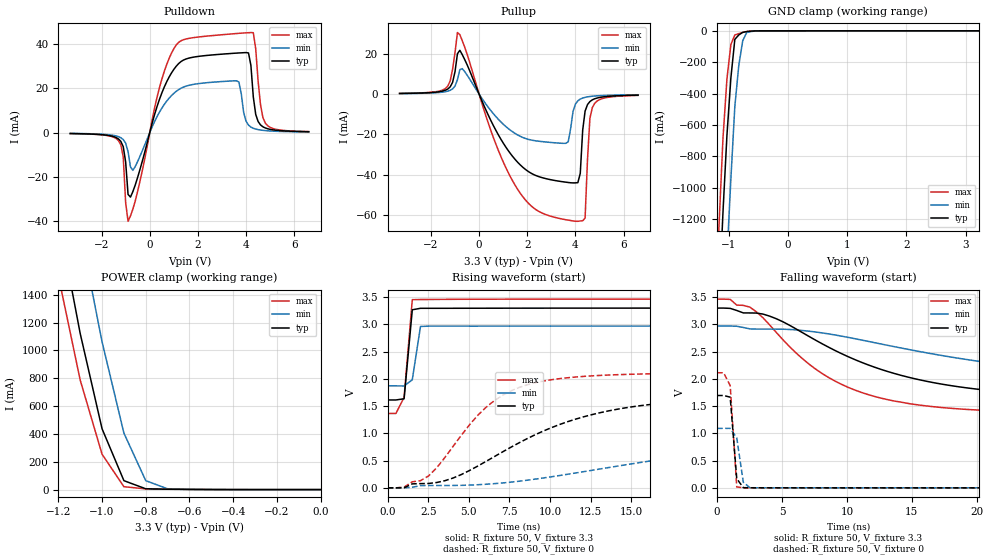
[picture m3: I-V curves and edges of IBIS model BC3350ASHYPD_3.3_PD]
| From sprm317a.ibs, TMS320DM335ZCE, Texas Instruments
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|   Component BC3350ASHYPD
|   Model Cell BC3350ASHYPD_3.3_PD
[Model]   BC3350ASHYPD_3.3_PD
Model_type   I/O
Polarity   Non-Inverting
Enable   Active-Low
Vinl =  1.5
Vinh =  1.8
Cref =  15.0000pF
Rref =  100.0000M
Vref =  0V
Vmeas =  1.65
C_comp   0.972592p   0.9599789p   0.9808023p
[Model Spec]
Vinl   1.5   1.335   1.5825
Vinh   1.8   1.635   1.8825
[Temperature Range]   25   125   -40
[Voltage Range]   3.3   2.97   3.465
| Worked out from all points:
|   slope of the pulldown table from 0 to 0.495 V, typ, clamps not added: 27.9 ohm
|   slope of the pullup table from 0 to 0.495 V, typ, clamps not added: 37.2 ohm
|   GND clamp passes 1 mA (typ) near -0.58 V on its own axis
|   POWER clamp passes 1 mA (typ) near -0.54 V on its own axis
|   rising waveform, R_fixture 50, V_fixture 3.3: 20-80 % time 313ps typ, 340ps min, 355ps max; typ from 1.61 V to 3.3 V
|   rising waveform, R_fixture 50, V_fixture 0: 20-80 % time 7.58ns typ, 16.6ns min, 3.87ns max; typ from 0 V to 1.69 V
|   falling waveform, R_fixture 50, V_fixture 3.3: 20-80 % time 10.4ns typ, 17.4ns min, 6.89ns max; typ from 3.3 V to 1.62 V
|   falling waveform, R_fixture 50, V_fixture 0: 20-80 % time 343ps typ, 407ps min, 344ps max; typ from 1.69 V to 0 V
[POWER_clamp]
|   voltage   I(typ)   I(min)   I(max)
-3.3V     22.26A     22.97A     21.87A
-1.2V     1.948A     2.725A     1.537A
-1.167V   1.673A     2.438A     1.287A
-1.133V   1.398A     2.15A      1.037A
-1.1V     1.122A     1.862A     787.5mA
-1.067V   894.2mA    1.595A     609.9mA
-1.033V   665.9mA    1.329A     432.2mA
-1V       437.5mA    1.062A     254.6mA
-900mV    64.3mA     406.1mA    20.83mA
-800mV    5.858mA    64.2mA     5.344mA
-700mV    2.683mA    5.806mA    3.281mA
-11.55fV  98.21uA    49.4uA     162.3uA
[Pulldown]
|   voltage   I(typ)   I(min)   I(max)
-3.3V     -400.6uA   -325.7uA   -416.4uA
-1.3V     -2.82mA    -1.791mA   -3.561mA
-1.1V     -6.344mA   -3.117mA   -10.94mA
-900mV    -27.92mA   -8.557mA   -40.06mA
-700mV    -26.62mA   -17.04mA   -34.57mA
400mV     14.94mA    9.202mA    20.18mA
1.1V      30.02mA    18.67mA    39.63mA
3.7V      36.02mA    22.92mA    44.89mA
4.2V      30.44mA    2.528mA    45.24mA
4.4V      8.262mA    1.627mA    37.92mA
4.8V      2.109mA    932uA      4.312mA
6.6V      432uA      310.9uA    478.4uA
[Pullup]
|   voltage   I(typ)   I(min)   I(max)
-3.3V     327.2uA    258.8uA    367uA
-1.3V     2.537mA    1.47mA     3.99mA
-900mV    20.03mA    7.177mA    30.58mA
-700mV    19.64mA    12.67mA    26.58mA
1.6V      -33.86mA   -20.29mA   -47.32mA
3.6V      -43.76mA   -24.45mA   -62.41mA
4.1V      -43.98mA   -3.317mA   -63.2mA
4.2V      -39.34mA   -2.467mA   -63.03mA
4.4V      -8.449mA   -1.61mA    -61.61mA
4.6V      -3.699mA   -1.187mA   -12mA
4.7V      -2.851mA   -1.047mA   -6.689mA
6.6V      -510.2uA   -319.1uA   -633uA
[GND_clamp]
|   voltage   I(typ)   I(min)   I(max)
-3.3V     -22.38A    -23.14A    -21.96A
-1.167V   -1.723A    -2.572A    -1.235A
-1.1V     -1.153A    -1.989A    -682mA
-1.033V   -666.3mA   -1.445A    -305.8mA
-966.7mV  -300mA     -942.5mA   -87.3mA
-900mV    -54.51mA   -482.5mA   -26.52mA
-833.3mV  -26.33mA   -220.7mA   -17.73mA
-766.7mV  -9.699mA   -63.44mA   -10.39mA
-700mV    -4.622mA   -10.61mA   -4.493mA
-566.7mV  -734.7uA   -1.505mA   -502.3uA
-433.3mV  -74.68uA   -170.1uA   -70.93uA
3.233V    98.2uA     61.6uA     162.2uA
[Ramp]
| variable   typ   min   max
dV/dt_f   1.009973/10.44558n   0.6341346/17.38728n   1.259403/6.880976n
dV/dt_r   1.016554/7.573793n   0.6368825/16.64163n   1.267372/3.857587n
R_load = 50
[Rising Waveform]
R_fixture = 50
V_fixture = 3.3
V_fixture_min = 2.97
V_fixture_max = 3.465
| time   V(typ)   V(min)   V(max)
|   time   V(typ)   V(min)   V(max)
0s        1.612V     1.871V     1.365V
505.1ps   1.612V     1.871V     1.365V
1.01ns    1.634V     1.87V      1.66V
1.515ns   3.267V     1.983V     3.452V
2.02ns    3.294V     2.96V      3.455V
2.525ns   3.294V     2.967V     3.456V
50ns      3.298V     2.969V     3.462V
[Rising Waveform]
R_fixture = 50
V_fixture = 0
V_fixture_min = 0
V_fixture_max = 0
| time   V(typ)   V(min)   V(max)
|   time   V(typ)   V(min)   V(max)
0s        57.9nV     466.6nV    5.467nV
2.525ns   80.82mV    43.28mV    220.2mV
4.04ns    181.8mV    43.91mV    765.9mV
6.566ns   572.3mV    76.97mV    1.599V
8.081ns   824.4mV    121.6mV    1.84V
10.1ns    1.106V     204mV      1.984V
14.14ns   1.442V     398.2mV    2.076V
19.7ns    1.61V      638.7mV    2.104V
32.32ns   1.684V     943.2mV    2.112V
50ns      1.694V     1.061V     2.112V
[Falling Waveform]
R_fixture = 50
V_fixture = 3.3
V_fixture_min = 2.97
V_fixture_max = 3.465
| time   V(typ)   V(min)   V(max)
|   time   V(typ)   V(min)   V(max)
0s        3.298V     2.969V     3.462V
2.525ns   3.209V     2.916V     3.316V
4.04ns    3.151V     2.912V     2.991V
6.566ns   2.849V     2.887V     2.371V
9.091ns   2.519V     2.804V     1.958V
11.62ns   2.258V     2.688V     1.712V
14.65ns   2.035V     2.544V     1.551V
19.7ns    1.82V      2.337V     1.433V
25.76ns   1.703V     2.163V     1.386V
50ns      1.616V     1.913V     1.365V
[Falling Waveform]
R_fixture = 50
V_fixture = 0
V_fixture_min = 0
V_fixture_max = 0
| time   V(typ)   V(min)   V(max)
|   time   V(typ)   V(min)   V(max)
0s        1.694V     1.091V     2.112V
505.1ps   1.694V     1.091V     2.112V
1.01ns    1.664V     1.092V     1.876V
1.515ns   169mV      915.3mV    16.5mV
2.02ns    3.416mV    103.3mV    2.289mV
2.525ns   1.446mV    3.7mV      1.33mV
50ns      922.3nV    11.66uV    68.52nV
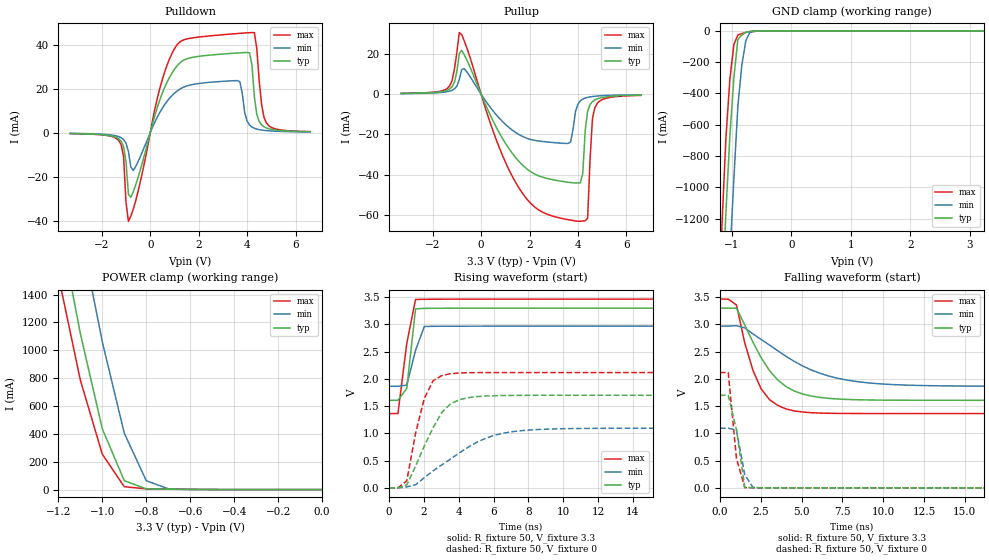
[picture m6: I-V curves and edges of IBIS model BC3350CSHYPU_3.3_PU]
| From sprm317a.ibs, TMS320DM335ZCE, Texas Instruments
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|   GS50 Cell BC3350CSHYPU
|   Model Cell BC3350CSHYPU_3.3_PU
[Model]   BC3350CSHYPU_3.3_PU
Model_type   I/O
Polarity   Non-Inverting
Enable   Active-Low
Vinl =  1.5
Vinh =  1.8
Cref =  15.0000pF
Rref =  100.0000M
Vref =  0V
Vmeas =  1.65
C_comp   0.972592p   0.9599789p   0.9808023p
[Model Spec]
Vinl   1.5   1.335   1.5825
Vinh   1.8   1.635   1.8825
[Temperature Range]   25   125   -40
[Voltage Range]   3.3   2.97   3.465
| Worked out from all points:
|   slope of the pulldown table from 0 to 0.495 V, typ, clamps not added: 27.7 ohm
|   slope of the pullup table from 0 to 0.495 V, typ, clamps not added: 37.2 ohm
|   GND clamp passes 1 mA (typ) near -0.58 V on its own axis
|   POWER clamp passes 1 mA (typ) near -0.55 V on its own axis
|   rising waveform, R_fixture 50, V_fixture 3.3: 20-80 % time 351ps typ, 605ps min, 587ps max; typ from 1.61 V to 3.3 V
|   rising waveform, R_fixture 50, V_fixture 0: 20-80 % time 1.55ns typ, 3.16ns min, 917ps max; typ from 0.001 V to 1.7 V
|   falling waveform, R_fixture 50, V_fixture 3.3: 20-80 % time 2.12ns typ, 3.91ns min, 1.37ns max; typ from 3.3 V to 1.61 V
|   falling waveform, R_fixture 50, V_fixture 0: 20-80 % time 582ps typ, 444ps min, 479ps max; typ from 1.7 V to 0.001 V
[POWER_clamp]
|   voltage   I(typ)   I(min)   I(max)
-3.3V     22.26A     22.97A     21.87A
-1.2V     1.947A     2.724A     1.536A
-1.167V   1.672A     2.436A     1.287A
-1.133V   1.397A     2.148A     1.037A
-1.1V     1.122A     1.86A      787.1mA
-1.067V   893.3mA    1.594A     609.5mA
-1.033V   665.2mA    1.327A     432mA
-1V       437mA      1.061A     254.5mA
-900mV    64.21mA    405.2mA    20.8mA
-800mV    5.835mA    63.97mA    5.284mA
-700mV    2.647mA    5.786mA    3.202mA
-11.55fV  459.3pA    9.252nA    230.6pA
[Pulldown]
|   voltage   I(typ)   I(min)   I(max)
-3.3V     -403.6uA   -328.8uA   -418.9uA
-1.3V     -2.841mA   -1.807mA   -3.581mA
-1.1V     -6.386mA   -3.145mA   -10.99mA
-900mV    -28.11mA   -8.625mA   -40.3mA
-700mV    -26.82mA   -17.2mA    -34.77mA
400mV     15.05mA    9.288mA    20.3mA
1.1V      30.25mA    18.85mA    39.86mA
3.7V      36.3mA     23.15mA    45.16mA
4.2V      30.68mA    2.555mA    45.51mA
4.4V      8.338mA    1.643mA    38.15mA
4.8V      2.127mA    941.5uA    4.342mA
6.6V      435.4uA    314uA      481.3uA
[Pullup]
|   voltage   I(typ)   I(min)   I(max)
-3.3V     327.4uA    259.3uA    367uA
-1.3V     2.541mA    1.473mA    3.994mA
-900mV    20.05mA    7.198mA    30.58mA
-700mV    19.65mA    12.69mA    26.57mA
1.6V      -33.88mA   -20.32mA   -47.31mA
3.6V      -43.79mA   -24.49mA   -62.4mA
4.1V      -44.01mA   -3.32mA    -63.19mA
4.2V      -39.34mA   -2.47mA    -63.02mA
4.4V      -8.445mA   -1.612mA   -61.59mA
4.6V      -3.699mA   -1.188mA   -11.99mA
4.7V      -2.851mA   -1.049mA   -6.684mA
6.6V      -510.5uA   -319.6uA   -632.9uA
[GND_clamp]
|   voltage   I(typ)   I(min)   I(max)
-3.3V     -22.38A    -23.15A    -21.96A
-1.167V   -1.724A    -2.574A    -1.236A
-1.1V     -1.155A    -1.991A    -683mA
-1.033V   -667.4mA   -1.447A    -306.4mA
-966.7mV  -300.8mA   -944.1mA   -87.57mA
-900mV    -54.73mA   -483.8mA   -26.57mA
-833.3mV  -26.43mA   -221.5mA   -17.78mA
-766.7mV  -9.741mA   -63.74mA   -10.43mA
-700mV    -4.66mA    -10.67mA   -4.538mA
-566.7mV  -780uA     -1.533mA   -563.3uA
-433.3mV  -131.6uA   -202.5uA   -150.5uA
3.233V    -4.373uA   23.83uA    -20.78uA
[Ramp]
| variable   typ   min   max
dV/dt_f   1.026357/2.114875n   0.6713871/3.942626n   1.272714/1.373508n
dV/dt_r   1.019438/1.521913n   0.6572379/3.143127n   1.269831/0.9080105n
R_load = 50
[Rising Waveform]
R_fixture = 50
V_fixture = 3.3
V_fixture_min = 2.97
V_fixture_max = 3.465
| time   V(typ)   V(min)   V(max)
|   time   V(typ)   V(min)   V(max)
0s        1.608V     1.865V     1.365V
505.1ps   1.608V     1.865V     1.365V
1.01ns    1.825V     1.886V     2.647V
1.515ns   3.286V     2.526V     3.459V
2.02ns    3.296V     2.963V     3.462V
50ns      3.3V       2.97V      3.465V
[Rising Waveform]
R_fixture = 50
V_fixture = 0
V_fixture_min = 0
V_fixture_max = 0
| time   V(typ)   V(min)   V(max)
|   time   V(typ)   V(min)   V(max)
0s        1.449mV    1.131mV    1.679mV
505.1ps   1.443mV    1.131mV    1.417mV
1.01ns    54.33mV    18.28mV    128.2mV
1.515ns   396.7mV    58.1mV     1.001V
2.02ns    769.8mV    188.1mV    1.644V
2.525ns   1.106V     314.4mV    1.967V
3.535ns   1.545V     532.7mV    2.096V
6.061ns   1.693V     966.8mV    2.117V
9.091ns   1.7V       1.079V     2.118V
50ns      1.7V       1.096V     2.118V
[Falling Waveform]
R_fixture = 50
V_fixture = 3.3
V_fixture_min = 2.97
V_fixture_max = 3.465
| time   V(typ)   V(min)   V(max)
|   time   V(typ)   V(min)   V(max)
0s        3.3V       2.97V      3.465V
1.01ns    3.298V     2.978V     3.358V
1.515ns   2.991V     2.937V     2.665V
2.02ns    2.674V     2.827V     2.157V
2.525ns   2.387V     2.723V     1.817V
3.535ns   1.983V     2.518V     1.515V
4.545ns   1.779V     2.323V     1.414V
7.576ns   1.626V     1.99V      1.367V
11.62ns   1.609V     1.885V     1.365V
50ns      1.608V     1.865V     1.365V
[Falling Waveform]
R_fixture = 50
V_fixture = 0
V_fixture_min = 0
V_fixture_max = 0
| time   V(typ)   V(min)   V(max)
|   time   V(typ)   V(min)   V(max)
0s        1.7V       1.096V     2.118V
505.1ps   1.7V       1.096V     2.118V
1.01ns    1.068V     1.059V     541.5mV
1.515ns   15.55mV    243.8mV    5.114mV
2.02ns    4.02mV     10.46mV    3.095mV
2.525ns   2.953mV    3.797mV    2.434mV
50ns      1.449mV    1.131mV    1.679mV
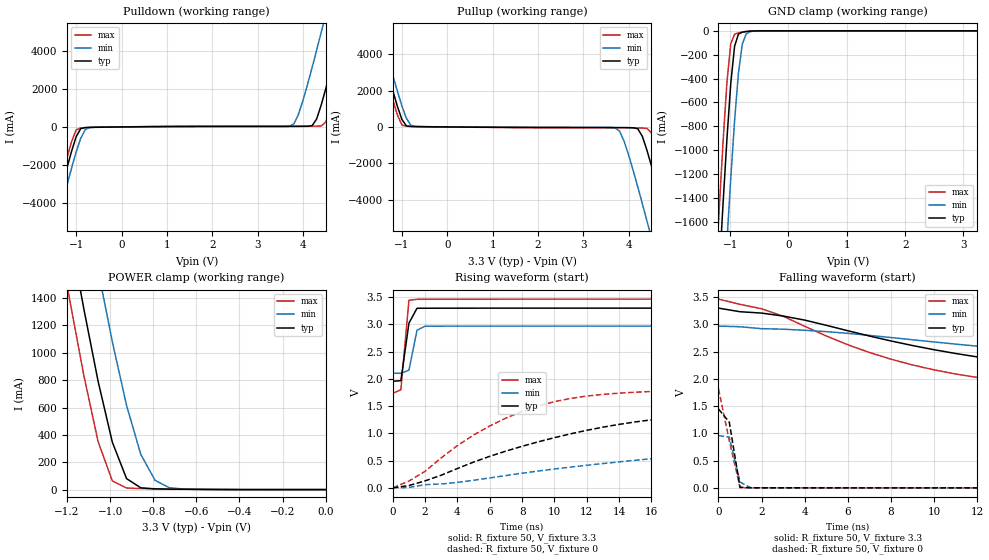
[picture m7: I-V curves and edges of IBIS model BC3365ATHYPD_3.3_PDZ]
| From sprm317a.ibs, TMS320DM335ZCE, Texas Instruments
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|   Component BC3365ATHYPD
|   Model Cell BC3365ATHYPD_3.3_PDZ
[Model]   BC3365ATHYPD_3.3_PDZ
Model_type   I/O
Polarity   Non-Inverting
Enable   Active-Low
Vinl =  1.5
Vinh =  1.8
Cref =  15.0000pF
Rref =  100.0000M
Vref =  0V
Vmeas =  1.65
C_comp   1.4550p   1.4591p   1.4542p
[Model Spec]
Vinl   1.5   1.335   1.5825
Vinh   1.8   1.635   1.8825
[Temperature Range]   25   125   -40
[Voltage Range]   3.3   2.97   3.465
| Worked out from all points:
|   slope of the pulldown table from 0 to 0.495 V, typ, clamps not added: 39.2 ohm
|   slope of the pullup table from 0 to 0.495 V, typ, clamps not added: 46.8 ohm
|   GND clamp passes 1 mA (typ) near -0.58 V on its own axis
|   POWER clamp passes 1 mA (typ) near -0.52 V on its own axis
|   rising waveform, R_fixture 50, V_fixture 3.3: 20-80 % time 389ps typ, 354ps min, 315ps max; typ from 1.96 V to 3.3 V
|   rising waveform, R_fixture 50, V_fixture 0: 20-80 % time 10.4ns typ, 19.8ns min, 6.25ns max; typ from 0 V to 1.45 V
|   falling waveform, R_fixture 50, V_fixture 3.3: 20-80 % time 11.2ns typ, 17.3ns min, 7.97ns max; typ from 3.3 V to 1.96 V
|   falling waveform, R_fixture 50, V_fixture 0: 20-80 % time 363ps typ, 348ps min, 601ps max; typ from 1.45 V to 0 V
[POWER_clamp]
|   voltage   I(typ)   I(min)   I(max)
-3.3V     22.37A     23.13A     21.95A
-1.254V   2.477A     3.334A     1.977A
-1.188V   1.887A     2.741A     1.389A
-1.122V   1.32A      2.163A     832.6mA
-1.056V   791.8mA    1.605A     350.4mA
-990mV    346.9mA    1.081A     63.79mA
-924mV    80.36mA    615.5mA    11.8mA
-858mV    13.13mA    257.6mA    7.543mA
-792mV    5.189mA    68.08mA    5.819mA
-726mV    3.556mA    14.04mA    4.359mA
-660mV    2.551mA    3.956mA    3.077mA
-7.994fV  477.5pA    13.59nA    225.3pA
[Pulldown]
|   voltage   I(typ)   I(min)   I(max)
-3.3V     -22.52A    -23.33A    -22.07A
-1.6V     -5.868A    -6.754A    -5.356A
-1.4V     -3.969A    -4.867A    -3.446A
-1.1V     -1.269A    -2.15A     -763.7mA
-900mV    -91.22mA   -600mA     -51.47mA
3.7V      28.47mA    32.98mA    36.63mA
3.9V      30.18mA    660.8mA    37.1mA
4.2V      65.76mA    3.119A     41.65mA
4.4V      1.143A     4.959A     50.6mA
4.8V      4.77A      8.763A     2.725A
5.1V      7.648A     11.66A     5.579A
6.6V      22.37A     26.38A     20.32A
[Pullup]
|   voltage   I(typ)   I(min)   I(max)
-3.3V     22.37A     23.13A     21.95A
-1.6V     5.722A     6.562A     5.242A
-1.5V     4.769A     5.616A     4.283A
-1V       414.3mA    1.161A     109.5mA
-700mV    19.39mA    18.75mA    25.39mA
3.7V      -34.43mA   -48.34mA   -45.92mA
3.9V      -35.85mA   -799.7mA   -46.23mA
4.2V      -101.1mA   -3.302A    -52.47mA
4.4V      -1.271A    -5.148A    -77.72mA
4.8V      -4.914A    -8.957A    -2.837A
5.1V      -7.794A    -11.86A    -5.694A
6.6V      -22.52A    -26.58A    -20.44A
[GND_clamp]
|   voltage   I(typ)   I(min)   I(max)
-3.3V     -22.52A    -23.33A    -22.07A
-1.254V   -2.615A    -3.518A    -2.087A
-1.188V   -2.022A    -2.922A    -1.495A
-1.122V   -1.449A    -2.338A    -932.9mA
-1.056V   -911mA     -1.774A    -435.1mA
-990mV    -443mA     -1.238A    -107.9mA
-924mV    -129.2mA   -751.9mA   -28.6mA
-858mV    -27.62mA   -355.1mA   -17.13mA
-792mV    -11.17mA   -111.8mA   -10.6mA
-726mV    -6.073mA   -26.07mA   -5.56mA
-660mV    -2.955mA   -7.156mA   -2.197mA
3.234V    -812.5pA   32.73uA    163.9pA
[Ramp]
| variable   typ   min   max
dV/dt_f   0.8063/11.2910n   0.5193/17.3295n   1.0372/7.9905n
dV/dt_r   0.8690/10.4137n   0.5758/19.8425n   1.0894/6.2291n
R_load = 50
[Rising Waveform]
R_fixture = 50
V_fixture = 3.3
V_fixture_min = 2.97
V_fixture_max = 3.465
| time   V(typ)   V(min)   V(max)
0s        1.958V     2.104V     1.736V
500ps     1.968V     2.103V     1.8V
1ns       3.026V     2.16V      3.445V
1.5ns     3.297V     2.895V     3.462V
2ns       3.298V     2.968V     3.463V
49.5ns    3.3V       2.97V      3.465V
[Rising Waveform]
R_fixture = 50
V_fixture = 0
V_fixture_min = 0
V_fixture_max = 0
|   time   V(typ)   V(min)   V(max)
0s        0V         0V         0V
2ns       128.3mV    58.6mV     304.5mV
4ns       355.5mV    100.7mV    776.8mV
7ns       675mV      226.4mV    1.281V
10ns      921.4mV    346.3mV    1.583V
14ns      1.165V     477mV      1.739V
18ns      1.309V     590mV      1.788V
22ns      1.379V     687.8mV    1.805V
39ns      1.444V     905.1mV    1.816V
99ns      1.448V     959.6mV    1.816V
[Falling Waveform]
R_fixture = 50
V_fixture = 3.3
V_fixture_min = 2.97
V_fixture_max = 3.465
|   time   V(typ)   V(min)   V(max)
0s        3.3V       2.97V      3.465V
2ns       3.209V     2.922V     3.288V
4ns       3.08V      2.893V     2.967V
6ns       2.885V     2.837V     2.628V
9ns       2.613V     2.719V     2.257V
13ns      2.349V     2.565V     1.974V
18ns      2.151V     2.41V      1.822V
26ns      2.017V     2.253V     1.753V
40ns      1.965V     2.143V     1.737V
99ns      1.958V     2.104V     1.736V
[Falling Waveform]
R_fixture = 50
V_fixture = 0
V_fixture_min = 0
V_fixture_max = 0
|   time   V(typ)   V(min)   V(max)
0s        1.448V     959.7mV    1.816V
500ps     1.207V     931.9mV    870mV
1ns       10.5mV     105.6mV    4mV
1.5ns     1.6mV      2mV        2mV
2ns       1.1mV      800uV      1mV
49.5ns    0V         0V         0V
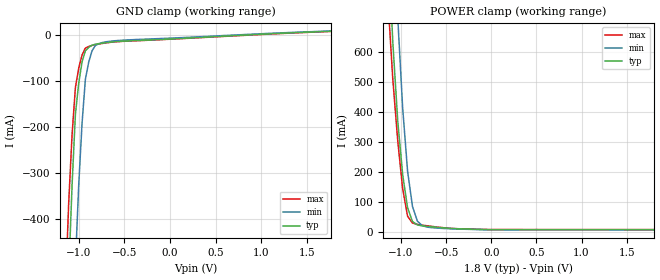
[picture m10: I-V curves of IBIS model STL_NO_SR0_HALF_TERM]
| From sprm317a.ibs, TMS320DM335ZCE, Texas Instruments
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|   Model Cell STL_NO_SR0_HALF_TERM
[Model]   STL_NO_SR0_HALF_TERM
Model_type   Input
Polarity   Non-Inverting
Vinl =  0.80
Vinh =  1.00
C_comp   2.680301p   2.549919p   2.900942p
[Model Spec]
Vinl   0.80   0.71   0.89
Vinh   1.00   0.91   1.09
[Temperature Range]   25   125   -40
[Voltage Range]   1.8   1.62   1.89
[POWER_clamp]
|   voltage   I(typ)   I(min)   I(max)
-1.8V     6.874A     7.433A     6.581A
-1.127V   863.6mA    1.359A     685.9mA
-1.109V   748mA      1.221A     597.3mA
-1.091V   632.5mA    1.084A     508.8mA
-1.036V   370.2mA    715.1mA    304.1mA
-1.018V   310.5mA    614.6mA    250.8mA
-981.8mV  191.1mA    413.7mA    144.1mA
-927.3mV  80.75mA    202.4mA    52.31mA
-872.7mV  34.47mA    84.58mA    29.44mA
-818.2mV  23.28mA    35.89mA    25.1mA
-654.5mV  16.79mA    14.05mA    18.26mA
1.8V      7.556mA    6.792mA    7.728mA
[GND_clamp]
|   voltage   I(typ)   I(min)   I(max)
-1.8V     -6.676A    -7.172A    -6.432A
-1.145V   -748.6mA   -1.247A    -551.2mA
-1.109V   -517.7mA   -978.2mA   -362.4mA
-1.073V   -325.9mA   -728.6mA   -216.9mA
-1.036V   -172.9mA   -497.6mA   -114.9mA
-1V       -105.1mA   -326.1mA   -72.69mA
-963.6mV  -59.22mA   -192.7mA   -44.16mA
-927.3mV  -35.2mA    -97.13mA   -29.3mA
-854.5mV  -23.13mA   -35.34mA   -23.48mA
-818.2mV  -20.92mA   -23.78mA   -21.92mA
-709.1mV  -17.7mA    -15.9mA    -18.23mA
1.764V    7.278mA    7.846mA    6.783mA
